One B-rep face of a CAD part: STEP entity #17.
In plain terms, the planar face has unit normal (0, -1, 0).
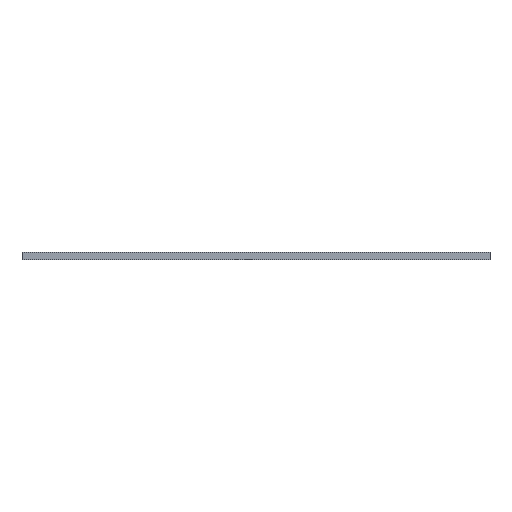
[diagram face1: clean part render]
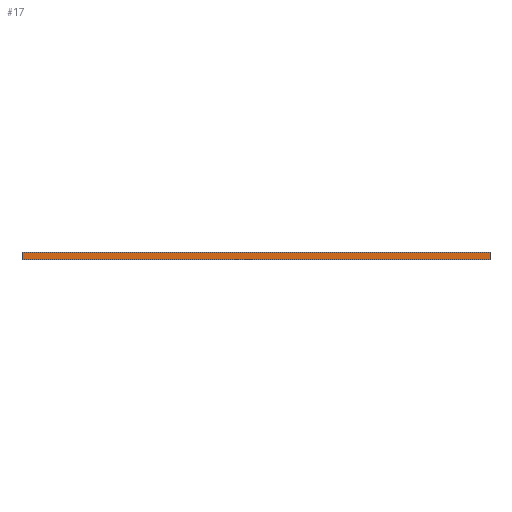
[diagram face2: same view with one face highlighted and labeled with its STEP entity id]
Its self-contained STEP definition (entity closure, numbers rounded to 3 decimals):
#17 = ADVANCED_FACE('',(#18),#32,.F.);
#18 = FACE_BOUND('',#19,.T.);
#19 = EDGE_LOOP('',(#20,#55,#83,#111));
#20 = ORIENTED_EDGE('',*,*,#21,.T.);
#21 = EDGE_CURVE('',#22,#24,#26,.T.);
#22 = VERTEX_POINT('',#23);
#23 = CARTESIAN_POINT('',(182.,-175.,0.));
#24 = VERTEX_POINT('',#25);
#25 = CARTESIAN_POINT('',(182.,-175.,6.));
#26 = SURFACE_CURVE('',#27,(#31,#43),.PCURVE_S1.);
#27 = LINE('',#28,#29);
#28 = CARTESIAN_POINT('',(182.,-175.,0.));
#29 = VECTOR('',#30,1.);
#30 = DIRECTION('',(-0.,-0.,1.));
#31 = PCURVE('',#32,#37);
#32 = PLANE('',#33);
#33 = AXIS2_PLACEMENT_3D('',#34,#35,#36);
#34 = CARTESIAN_POINT('',(182.,-175.,0.));
#35 = DIRECTION('',(-0.,1.,-0.));
#36 = DIRECTION('',(1.,0.,0.));
#37 = DEFINITIONAL_REPRESENTATION('',(#38),#42);
#38 = LINE('',#39,#40);
#39 = CARTESIAN_POINT('',(-0.,-0.));
#40 = VECTOR('',#41,1.);
#41 = DIRECTION('',(-0.,-1.));
#42 = ( GEOMETRIC_REPRESENTATION_CONTEXT(2) 
PARAMETRIC_REPRESENTATION_CONTEXT() REPRESENTATION_CONTEXT('2D SPACE',''
  ) );
#43 = PCURVE('',#44,#49);
#44 = PLANE('',#45);
#45 = AXIS2_PLACEMENT_3D('',#46,#47,#48);
#46 = CARTESIAN_POINT('',(182.,175.,0.));
#47 = DIRECTION('',(-1.,-0.,-0.));
#48 = DIRECTION('',(0.,1.,0.));
#49 = DEFINITIONAL_REPRESENTATION('',(#50),#54);
#50 = LINE('',#51,#52);
#51 = CARTESIAN_POINT('',(-350.,0.));
#52 = VECTOR('',#53,1.);
#53 = DIRECTION('',(-0.,-1.));
#54 = ( GEOMETRIC_REPRESENTATION_CONTEXT(2) 
PARAMETRIC_REPRESENTATION_CONTEXT() REPRESENTATION_CONTEXT('2D SPACE',''
  ) );
#55 = ORIENTED_EDGE('',*,*,#56,.T.);
#56 = EDGE_CURVE('',#24,#57,#59,.T.);
#57 = VERTEX_POINT('',#58);
#58 = CARTESIAN_POINT('',(-182.,-175.,6.));
#59 = SURFACE_CURVE('',#60,(#64,#71),.PCURVE_S1.);
#60 = LINE('',#61,#62);
#61 = CARTESIAN_POINT('',(182.,-175.,6.));
#62 = VECTOR('',#63,1.);
#63 = DIRECTION('',(-1.,-0.,-0.));
#64 = PCURVE('',#32,#65);
#65 = DEFINITIONAL_REPRESENTATION('',(#66),#70);
#66 = LINE('',#67,#68);
#67 = CARTESIAN_POINT('',(-0.,-6.));
#68 = VECTOR('',#69,1.);
#69 = DIRECTION('',(-1.,0.));
#70 = ( GEOMETRIC_REPRESENTATION_CONTEXT(2) 
PARAMETRIC_REPRESENTATION_CONTEXT() REPRESENTATION_CONTEXT('2D SPACE',''
  ) );
#71 = PCURVE('',#72,#77);
#72 = PLANE('',#73);
#73 = AXIS2_PLACEMENT_3D('',#74,#75,#76);
#74 = CARTESIAN_POINT('',(0.,0.,6.));
#75 = DIRECTION('',(-0.,-0.,1.));
#76 = DIRECTION('',(1.,0.,0.));
#77 = DEFINITIONAL_REPRESENTATION('',(#78),#82);
#78 = LINE('',#79,#80);
#79 = CARTESIAN_POINT('',(182.,-175.));
#80 = VECTOR('',#81,1.);
#81 = DIRECTION('',(-1.,0.));
#82 = ( GEOMETRIC_REPRESENTATION_CONTEXT(2) 
PARAMETRIC_REPRESENTATION_CONTEXT() REPRESENTATION_CONTEXT('2D SPACE',''
  ) );
#83 = ORIENTED_EDGE('',*,*,#84,.F.);
#84 = EDGE_CURVE('',#85,#57,#87,.T.);
#85 = VERTEX_POINT('',#86);
#86 = CARTESIAN_POINT('',(-182.,-175.,0.));
#87 = SURFACE_CURVE('',#88,(#92,#99),.PCURVE_S1.);
#88 = LINE('',#89,#90);
#89 = CARTESIAN_POINT('',(-182.,-175.,0.));
#90 = VECTOR('',#91,1.);
#91 = DIRECTION('',(-0.,-0.,1.));
#92 = PCURVE('',#32,#93);
#93 = DEFINITIONAL_REPRESENTATION('',(#94),#98);
#94 = LINE('',#95,#96);
#95 = CARTESIAN_POINT('',(-364.,0.));
#96 = VECTOR('',#97,1.);
#97 = DIRECTION('',(-0.,-1.));
#98 = ( GEOMETRIC_REPRESENTATION_CONTEXT(2) 
PARAMETRIC_REPRESENTATION_CONTEXT() REPRESENTATION_CONTEXT('2D SPACE',''
  ) );
#99 = PCURVE('',#100,#105);
#100 = PLANE('',#101);
#101 = AXIS2_PLACEMENT_3D('',#102,#103,#104);
#102 = CARTESIAN_POINT('',(-182.,-175.,0.));
#103 = DIRECTION('',(1.,-0.,-0.));
#104 = DIRECTION('',(0.,-1.,0.));
#105 = DEFINITIONAL_REPRESENTATION('',(#106),#110);
#106 = LINE('',#107,#108);
#107 = CARTESIAN_POINT('',(-0.,-0.));
#108 = VECTOR('',#109,1.);
#109 = DIRECTION('',(-0.,-1.));
#110 = ( GEOMETRIC_REPRESENTATION_CONTEXT(2) 
PARAMETRIC_REPRESENTATION_CONTEXT() REPRESENTATION_CONTEXT('2D SPACE',''
  ) );
#111 = ORIENTED_EDGE('',*,*,#112,.F.);
#112 = EDGE_CURVE('',#22,#85,#113,.T.);
#113 = SURFACE_CURVE('',#114,(#118,#125),.PCURVE_S1.);
#114 = LINE('',#115,#116);
#115 = CARTESIAN_POINT('',(182.,-175.,0.));
#116 = VECTOR('',#117,1.);
#117 = DIRECTION('',(-1.,-0.,-0.));
#118 = PCURVE('',#32,#119);
#119 = DEFINITIONAL_REPRESENTATION('',(#120),#124);
#120 = LINE('',#121,#122);
#121 = CARTESIAN_POINT('',(-0.,-0.));
#122 = VECTOR('',#123,1.);
#123 = DIRECTION('',(-1.,0.));
#124 = ( GEOMETRIC_REPRESENTATION_CONTEXT(2) 
PARAMETRIC_REPRESENTATION_CONTEXT() REPRESENTATION_CONTEXT('2D SPACE',''
  ) );
#125 = PCURVE('',#126,#131);
#126 = PLANE('',#127);
#127 = AXIS2_PLACEMENT_3D('',#128,#129,#130);
#128 = CARTESIAN_POINT('',(0.,0.,0.));
#129 = DIRECTION('',(-0.,-0.,1.));
#130 = DIRECTION('',(1.,0.,0.));
#131 = DEFINITIONAL_REPRESENTATION('',(#132),#136);
#132 = LINE('',#133,#134);
#133 = CARTESIAN_POINT('',(182.,-175.));
#134 = VECTOR('',#135,1.);
#135 = DIRECTION('',(-1.,0.));
#136 = ( GEOMETRIC_REPRESENTATION_CONTEXT(2) 
PARAMETRIC_REPRESENTATION_CONTEXT() REPRESENTATION_CONTEXT('2D SPACE',''
  ) );
